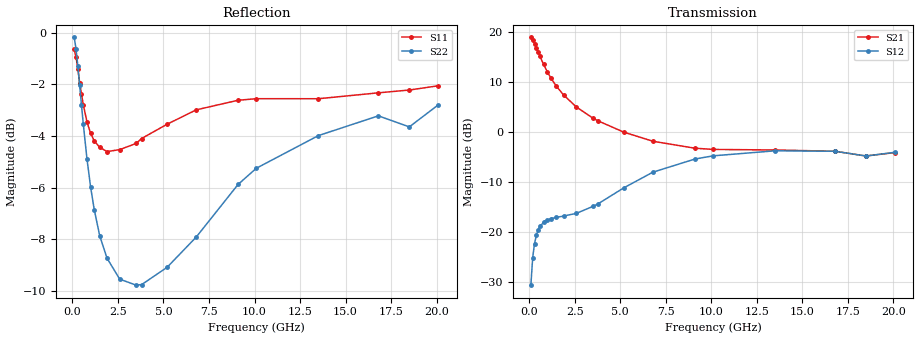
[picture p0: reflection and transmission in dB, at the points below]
!  Infineon Technologies AG
! BFR380L3 , PF131585-7, No.6, Th 09.10.01, soldered on pcb-board, measured with PP GSG850
!  Vce=3.0 V,  Ic=2.5 mA
! Common Emitter S-Parameters:  15. November 2001
#  GHz  S  MA  R  50
! f  S11  S21  S12  S22
! GHz  Mag  Ang  Mag  Ang  Mag  Ang  Mag  Ang
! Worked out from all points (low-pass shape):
!   201 points, 100 MHz to 20.1 GHz, reference 50 ohm
!   highest |S21| = 18.90 dB at 100 MHz (marker M1); lowest = -4.8 dB at 18.5 GHz (marker M2)
!   |S21| within 3 dB of the highest: start of sweep to 509.2 MHz
!   lowest |S11| = -4.6 dB at 1.9 GHz (marker M3), VSWR 3.86, Z = 13.1 - j4.95 ohm
!   |S11| at or under -10 dB: nowhere
!   |S22| runs from -9.8 to -0.2 dB; largest |S21 - S12| = 8.8
!   S11 on the Smith chart (normalised r, x): 100 MHz: 1.25, -5.56; 500 MHz: 0.31, -1.10; 1.2 GHz: 0.27, -0.35; 3.8 GHz: 0.25, +0.27; 9.1 GHz: 0.33, +1.06; 20.1 GHz: 1.00, +2.56
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0.1  0.9279 -19.4  8.806 166.7  0.02975 77.9  0.979 -10.5
0.2  0.8967 -37.4  8.229 154.6  0.05602 69.3  0.9299 -20.1
0.3  0.8504 -54.5  7.618 143.6  0.07723 60.7  0.8619 -28.3
0.4  0.8001 -69.3  6.943 134.2  0.09345 53.8  0.7907 -35.1
0.5  0.7607 -82.0  6.291 126.1  0.1055 48.3  0.724 -40.5
0.6  0.725 -93.5  5.693 119.2  0.1145 44.0  0.6645 -44.8
0.8  0.6722 -112.1  4.726 108.0  0.1261 38.0  0.5701 -51.1
1  0.6386 -126.7  4.003 99.3  0.1327 34.3  0.5027 -55.6
1.2  0.6173 -138.7  3.458 92.1  0.1371 32.2  0.4545 -59.0
1.5  0.5998 -153.0  2.872 83.1  0.1411 31.0  0.4046 -63.4
1.9  0.5886 -167.9  2.34 73.0  0.1454 31.8  0.3661 -68.7
2.6  0.5937 172.8  1.78 58.8  0.1547 36.4  0.3333 -79.1
3.5  0.6102 153.6  1.381 43.7  0.1813 44.1  0.3246 -94.4
3.8  0.6238 148.4  1.292 39.6  0.193 45.9  0.3253 -100.7
5.2  0.6649 126.5  0.9991 22.8  0.2777 48.2  0.3514 -128.9
6.8  0.7088 105.5  0.8104 10.0  0.3983 41.3  0.4021 -163.1
9.1  0.7398 83.8  0.6908 -0.4  0.5381 23.7  0.5085 157.1
10.1  0.745 76.1  0.6717 -4.0  0.5796 15.8  0.5464 142.2
13.5  0.7448 58.2  0.6631 -17.8  0.6505 -8.5  0.6318 104.4
16.8  0.7647 46.7  0.6438 -30.8  0.6442 -25.6  0.6902 79.5
18.5  0.7743 45.1  0.5774 -38.2  0.5771 -34.3  0.657 73.2
20.1  0.7892 38.0  0.6254 -42.0  0.6292 -39.5  0.7252 62.0
